VERSION 5.7 ;
  NOWIREEXTENSIONATPIN ON ;
  DIVIDERCHAR "/" ;
  BUSBITCHARS "[]" ;
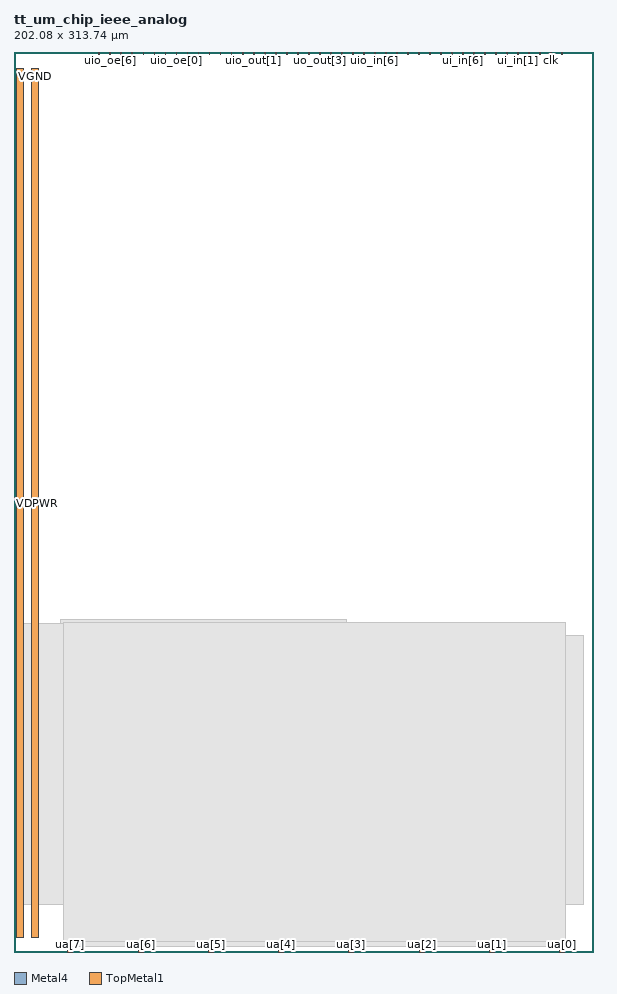
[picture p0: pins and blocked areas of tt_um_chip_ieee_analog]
MACRO tt_um_chip_ieee_analog
  CLASS BLOCK ;
  FOREIGN tt_um_chip_ieee_analog ;
  ORIGIN 0.000 0.000 ;
  SIZE 202.080 BY 313.740 ;
  PIN clk
    PORT
      LAYER Metal4 ;
        RECT 187.050 312.740 187.350 313.740 ;
    END
  END clk
  PIN ena
    PORT
      LAYER Metal4 ;
        RECT 190.890 312.740 191.190 313.740 ;
    END
  END ena
  PIN rst_n
    PORT
      LAYER Metal4 ;
        RECT 183.210 312.740 183.510 313.740 ;
    END
  END rst_n
  PIN ui_in[0]
    PORT
      LAYER Metal4 ;
        RECT 179.370 312.740 179.670 313.740 ;
    END
  END ui_in[0]
  PIN ui_in[1]
    PORT
      LAYER Metal4 ;
        RECT 175.530 312.740 175.830 313.740 ;
    END
  END ui_in[1]
  PIN ui_in[2]
    PORT
      LAYER Metal4 ;
        RECT 171.690 312.740 171.990 313.740 ;
    END
  END ui_in[2]
  PIN ui_in[3]
    PORT
      LAYER Metal4 ;
        RECT 167.850 312.740 168.150 313.740 ;
    END
  END ui_in[3]
  PIN ui_in[4]
    PORT
      LAYER Metal4 ;
        RECT 164.010 312.740 164.310 313.740 ;
    END
  END ui_in[4]
  PIN ui_in[5]
    PORT
      LAYER Metal4 ;
        RECT 160.170 312.740 160.470 313.740 ;
    END
  END ui_in[5]
  PIN ui_in[6]
    PORT
      LAYER Metal4 ;
        RECT 156.330 312.740 156.630 313.740 ;
    END
  END ui_in[6]
  PIN ui_in[7]
    PORT
      LAYER Metal4 ;
        RECT 152.490 312.740 152.790 313.740 ;
    END
  END ui_in[7]
  PIN uio_in[0]
    PORT
      LAYER Metal4 ;
        RECT 148.650 312.740 148.950 313.740 ;
    END
  END uio_in[0]
  PIN uio_in[1]
    PORT
      LAYER Metal4 ;
        RECT 144.810 312.740 145.110 313.740 ;
    END
  END uio_in[1]
  PIN uio_in[2]
    PORT
      LAYER Metal4 ;
        RECT 140.970 312.740 141.270 313.740 ;
    END
  END uio_in[2]
  PIN uio_in[3]
    PORT
      LAYER Metal4 ;
        RECT 137.130 312.740 137.430 313.740 ;
    END
  END uio_in[3]
  PIN uio_in[4]
    PORT
      LAYER Metal4 ;
        RECT 133.290 312.740 133.590 313.740 ;
    END
  END uio_in[4]
  PIN uio_in[5]
    PORT
      LAYER Metal4 ;
        RECT 129.450 312.740 129.750 313.740 ;
    END
  END uio_in[5]
  PIN uio_in[6]
    PORT
      LAYER Metal4 ;
        RECT 125.610 312.740 125.910 313.740 ;
    END
  END uio_in[6]
  PIN uio_in[7]
    PORT
      LAYER Metal4 ;
        RECT 121.770 312.740 122.070 313.740 ;
    END
  END uio_in[7]
  PIN uio_oe[0]
    PORT
      LAYER Metal4 ;
        RECT 56.490 312.740 56.790 313.740 ;
    END
  END uio_oe[0]
  PIN uio_oe[1]
    PORT
      LAYER Metal4 ;
        RECT 52.650 312.740 52.950 313.740 ;
    END
  END uio_oe[1]
  PIN uio_oe[2]
    PORT
      LAYER Metal4 ;
        RECT 48.810 312.740 49.110 313.740 ;
    END
  END uio_oe[2]
  PIN uio_oe[3]
    PORT
      LAYER Metal4 ;
        RECT 44.970 312.740 45.270 313.740 ;
    END
  END uio_oe[3]
  PIN uio_oe[4]
    PORT
      LAYER Metal4 ;
        RECT 41.130 312.740 41.430 313.740 ;
    END
  END uio_oe[4]
  PIN uio_oe[5]
    PORT
      LAYER Metal4 ;
        RECT 37.290 312.740 37.590 313.740 ;
    END
  END uio_oe[5]
  PIN uio_oe[6]
    PORT
      LAYER Metal4 ;
        RECT 33.450 312.740 33.750 313.740 ;
    END
  END uio_oe[6]
  PIN uio_oe[7]
    PORT
      LAYER Metal4 ;
        RECT 29.610 312.740 29.910 313.740 ;
    END
  END uio_oe[7]
  PIN uio_out[0]
    PORT
      LAYER Metal4 ;
        RECT 87.210 312.740 87.510 313.740 ;
    END
  END uio_out[0]
  PIN uio_out[1]
    PORT
      LAYER Metal4 ;
        RECT 83.370 312.740 83.670 313.740 ;
    END
  END uio_out[1]
  PIN uio_out[2]
    PORT
      LAYER Metal4 ;
        RECT 79.530 312.740 79.830 313.740 ;
    END
  END uio_out[2]
  PIN uio_out[3]
    PORT
      LAYER Metal4 ;
        RECT 75.690 312.740 75.990 313.740 ;
    END
  END uio_out[3]
  PIN uio_out[4]
    PORT
      LAYER Metal4 ;
        RECT 71.850 312.740 72.150 313.740 ;
    END
  END uio_out[4]
  PIN uio_out[5]
    PORT
      LAYER Metal4 ;
        RECT 68.010 312.740 68.310 313.740 ;
    END
  END uio_out[5]
  PIN uio_out[6]
    PORT
      LAYER Metal4 ;
        RECT 64.170 312.740 64.470 313.740 ;
    END
  END uio_out[6]
  PIN uio_out[7]
    PORT
      LAYER Metal4 ;
        RECT 60.330 312.740 60.630 313.740 ;
    END
  END uio_out[7]
  PIN uo_out[0]
    PORT
      LAYER Metal4 ;
        RECT 117.930 312.740 118.230 313.740 ;
    END
  END uo_out[0]
  PIN uo_out[1]
    PORT
      LAYER Metal4 ;
        RECT 114.090 312.740 114.390 313.740 ;
    END
  END uo_out[1]
  PIN uo_out[2]
    PORT
      LAYER Metal4 ;
        RECT 110.250 312.740 110.550 313.740 ;
    END
  END uo_out[2]
  PIN uo_out[3]
    PORT
      LAYER Metal4 ;
        RECT 106.410 312.740 106.710 313.740 ;
    END
  END uo_out[3]
  PIN uo_out[4]
    PORT
      LAYER Metal4 ;
        RECT 102.570 312.740 102.870 313.740 ;
    END
  END uo_out[4]
  PIN uo_out[5]
    PORT
      LAYER Metal4 ;
        RECT 98.730 312.740 99.030 313.740 ;
    END
  END uo_out[5]
  PIN uo_out[6]
    PORT
      LAYER Metal4 ;
        RECT 94.890 312.740 95.190 313.740 ;
    END
  END uo_out[6]
  PIN uo_out[7]
    PORT
      LAYER Metal4 ;
        RECT 91.050 312.740 91.350 313.740 ;
    END
  END uo_out[7]
  PIN ua[0]
    ANTENNAGATEAREA 322.334991 ;
    ANTENNADIFFAREA 14.250000 ;
    PORT
      LAYER TopMetal1 ;
        RECT 190.165 0.000 191.915 2.000 ;
    END
  END ua[0]
  PIN ua[1]
    ANTENNADIFFAREA 3.040000 ;
    PORT
      LAYER TopMetal1 ;
        RECT 165.685 0.000 167.435 2.000 ;
    END
  END ua[1]
  PIN ua[2]
    ANTENNAGATEAREA 230.000000 ;
    ANTENNADIFFAREA 19.722000 ;
    PORT
      LAYER TopMetal1 ;
        RECT 141.205 0.000 142.955 2.000 ;
    END
  END ua[2]
  PIN ua[3]
    PORT
      LAYER TopMetal1 ;
        RECT 116.725 0.000 118.475 2.000 ;
    END
  END ua[3]
  PIN ua[4]
    PORT
      LAYER TopMetal1 ;
        RECT 92.245 0.000 93.995 2.000 ;
    END
  END ua[4]
  PIN ua[5]
    PORT
      LAYER TopMetal1 ;
        RECT 67.765 0.000 69.515 2.000 ;
    END
  END ua[5]
  PIN ua[6]
    PORT
      LAYER TopMetal1 ;
        RECT 43.285 0.000 45.035 2.000 ;
    END
  END ua[6]
  PIN ua[7]
    PORT
      LAYER TopMetal1 ;
        RECT 18.805 0.000 20.555 2.000 ;
    END
  END ua[7]
  PIN VDPWR
    DIRECTION INOUT ;
    USE POWER ;
    ANTENNAGATEAREA 107.743996 ;
    ANTENNADIFFAREA 289.751984 ;
    PORT
      LAYER TopMetal1 ;
        RECT 1.000 5.000 3.400 308.000 ;
    END
  END VDPWR
  PIN VGND
    DIRECTION INOUT ;
    USE GROUND ;
    ANTENNADIFFAREA 202.139694 ;
    PORT
      LAYER TopMetal1 ;
        RECT 6.000 5.000 8.400 308.000 ;
    END
  END VGND
  OBS
      LAYER GatPoly ;
        RECT 21.675 41.765 110.070 110.705 ;
      LAYER Metal1 ;
        RECT 16.200 16.390 116.010 115.830 ;
      LAYER Metal2 ;
        RECT 16.200 16.390 116.010 115.830 ;
      LAYER Metal3 ;
        RECT 17.340 16.390 114.875 110.315 ;
      LAYER Metal4 ;
        RECT 17.340 16.390 198.370 110.315 ;
      LAYER Metal5 ;
        RECT 1.000 16.390 191.915 114.370 ;
      LAYER TopMetal1 ;
        RECT 17.340 3.640 192.170 114.690 ;
        RECT 22.195 2.000 41.645 3.640 ;
        RECT 46.675 2.000 66.125 3.640 ;
        RECT 71.155 2.000 90.605 3.640 ;
        RECT 95.635 2.000 115.085 3.640 ;
        RECT 120.115 2.000 139.565 3.640 ;
        RECT 144.595 2.000 164.045 3.640 ;
        RECT 169.075 2.000 188.525 3.640 ;
  END
END tt_um_chip_ieee_analog
END LIBRARY

